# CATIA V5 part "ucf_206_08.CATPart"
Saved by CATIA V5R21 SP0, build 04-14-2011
Part number: ucf_206_08
Bounding box of the stored display mesh (mm): x -25.531 to 25.531, y -8.1 to -6.5, z -25.345 to 25.345
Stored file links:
  C:\TPO v2\SharedFS\Outgoing\ucf_206_08.CATPart

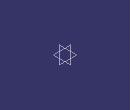
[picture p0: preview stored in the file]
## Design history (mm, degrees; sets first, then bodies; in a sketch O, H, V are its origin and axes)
AxisSystem1: origin (0, 0, 0), X (1, 0, 0), Y (0, 1, 0), Z (0, 0, 1)
Body1 "ucf_206_08" (main body)
  Solid1: solid without history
